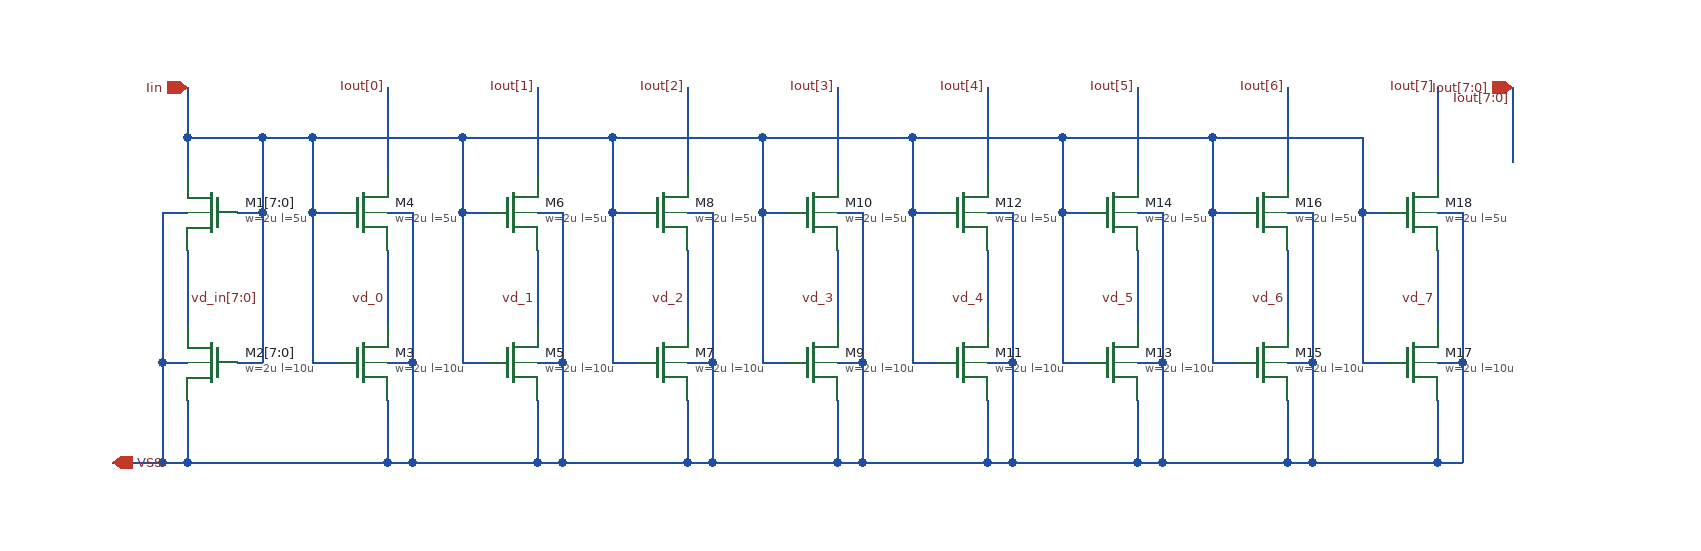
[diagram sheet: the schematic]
v {xschem version=3.4.7 file_version=1.2}
G {}
K {}
V {}
S {}
E {}
N 420 -320 440 -320 {lab=VSS}
N 420 -200 440 -200 {lab=VSS}
N 440 -320 440 -200 {lab=VSS}
N 420 -290 420 -230 {lab=vd_1}
N 300 -290 300 -230 {lab=vd_0}
N 140 -290 140 -230 {lab=vd_in[7:0]}
N 420 -170 420 -120 {lab=VSS}
N 140 -170 140 -120 {lab=VSS}
N 300 -170 300 -120 {lab=VSS}
N 300 -320 320 -320 {lab=VSS}
N 300 -200 320 -200 {lab=VSS}
N 320 -320 320 -200 {lab=VSS}
N 120 -320 140 -320 {lab=VSS}
N 120 -200 140 -200 {lab=VSS}
N 120 -320 120 -200 {lab=VSS}
N 140 -380 140 -350 {lab=Iin}
N 360 -320 360 -200 {lab=Iin}
N 360 -200 380 -200 {lab=Iin}
N 360 -320 380 -320 {lab=Iin}
N 360 -380 360 -320 {lab=Iin}
N 240 -320 240 -200 {lab=Iin}
N 240 -200 260 -200 {lab=Iin}
N 240 -320 260 -320 {lab=Iin}
N 240 -380 240 -320 {lab=Iin}
N 200 -320 200 -200 {lab=Iin}
N 180 -200 200 -200 {lab=Iin}
N 180 -320 200 -320 {lab=Iin}
N 200 -380 200 -320 {lab=Iin}
N 140 -380 200 -380 {lab=Iin}
N 120 -120 140 -120 {lab=VSS}
N 140 -420 140 -380 {lab=Iin}
N 300 -420 300 -350 {lab=Iout[0]}
N 420 -420 420 -350 {lab=Iout[1]}
N 120 -200 120 -120 {lab=VSS}
N 140 -120 300 -120 {lab=VSS}
N 200 -380 240 -380 {lab=Iin}
N 320 -120 420 -120 {lab=VSS}
N 240 -380 360 -380 {lab=Iin}
N 320 -200 320 -120 {lab=VSS}
N 300 -120 320 -120 {lab=VSS}
N 440 -200 440 -120 {lab=VSS}
N 660 -320 680 -320 {lab=VSS}
N 660 -200 680 -200 {lab=VSS}
N 680 -320 680 -200 {lab=VSS}
N 660 -290 660 -230 {lab=vd_3}
N 540 -290 540 -230 {lab=vd_2}
N 660 -170 660 -120 {lab=VSS}
N 540 -170 540 -120 {lab=VSS}
N 540 -320 560 -320 {lab=VSS}
N 540 -200 560 -200 {lab=VSS}
N 560 -320 560 -200 {lab=VSS}
N 600 -320 600 -200 {lab=Iin}
N 600 -200 620 -200 {lab=Iin}
N 600 -320 620 -320 {lab=Iin}
N 600 -380 600 -320 {lab=Iin}
N 480 -320 480 -200 {lab=Iin}
N 480 -200 500 -200 {lab=Iin}
N 480 -320 500 -320 {lab=Iin}
N 480 -380 480 -320 {lab=Iin}
N 600 -380 720 -380 {lab=Iin}
N 540 -420 540 -350 {lab=Iout[2]}
N 660 -420 660 -350 {lab=Iout[3]}
N 660 -120 680 -120 {lab=VSS}
N 560 -120 660 -120 {lab=VSS}
N 480 -380 600 -380 {lab=Iin}
N 560 -200 560 -120 {lab=VSS}
N 540 -120 560 -120 {lab=VSS}
N 680 -200 680 -120 {lab=VSS}
N 900 -320 920 -320 {lab=VSS}
N 900 -200 920 -200 {lab=VSS}
N 920 -320 920 -200 {lab=VSS}
N 900 -290 900 -230 {lab=vd_5}
N 780 -290 780 -230 {lab=vd_4}
N 900 -170 900 -120 {lab=VSS}
N 780 -170 780 -120 {lab=VSS}
N 780 -320 800 -320 {lab=VSS}
N 780 -200 800 -200 {lab=VSS}
N 800 -320 800 -200 {lab=VSS}
N 840 -320 840 -200 {lab=Iin}
N 840 -200 860 -200 {lab=Iin}
N 840 -320 860 -320 {lab=Iin}
N 840 -380 840 -320 {lab=Iin}
N 720 -320 720 -200 {lab=Iin}
N 720 -200 740 -200 {lab=Iin}
N 720 -320 740 -320 {lab=Iin}
N 720 -380 720 -320 {lab=Iin}
N 840 -380 960 -380 {lab=Iin}
N 780 -420 780 -350 {lab=Iout[4]}
N 900 -420 900 -350 {lab=Iout[5]}
N 900 -120 920 -120 {lab=VSS}
N 800 -120 900 -120 {lab=VSS}
N 720 -380 840 -380 {lab=Iin}
N 800 -200 800 -120 {lab=VSS}
N 780 -120 800 -120 {lab=VSS}
N 920 -200 920 -120 {lab=VSS}
N 1140 -320 1160 -320 {lab=VSS}
N 1140 -200 1160 -200 {lab=VSS}
N 1160 -320 1160 -200 {lab=VSS}
N 1140 -290 1140 -230 {lab=vd_7}
N 1020 -290 1020 -230 {lab=vd_6}
N 1140 -170 1140 -120 {lab=VSS}
N 1020 -170 1020 -120 {lab=VSS}
N 1020 -320 1040 -320 {lab=VSS}
N 1020 -200 1040 -200 {lab=VSS}
N 1040 -320 1040 -200 {lab=VSS}
N 1080 -320 1080 -200 {lab=Iin}
N 1080 -200 1100 -200 {lab=Iin}
N 1080 -320 1100 -320 {lab=Iin}
N 1080 -380 1080 -320 {lab=Iin}
N 960 -320 960 -200 {lab=Iin}
N 960 -200 980 -200 {lab=Iin}
N 960 -320 980 -320 {lab=Iin}
N 960 -380 960 -320 {lab=Iin}
N 1020 -420 1020 -350 {lab=Iout[6]}
N 1140 -420 1140 -350 {lab=Iout[0]}
N 1140 -120 1160 -120 {lab=VSS}
N 1040 -120 1140 -120 {lab=VSS}
N 960 -380 1080 -380 {lab=Iin}
N 1040 -200 1040 -120 {lab=VSS}
N 1020 -120 1040 -120 {lab=VSS}
N 1160 -200 1160 -120 {lab=VSS}
N 360 -380 480 -380 {lab=Iin}
N 440 -120 540 -120 {lab=VSS}
N 680 -120 780 -120 {lab=VSS}
N 920 -120 1020 -120 {lab=VSS}
N 420 -120 440 -120 {lab=VSS}
N 80 -120 120 -120 {lab=VSS}
N 1200 -420 1200 -360 {lab=Iout[7:0]}
C {title.sym} 160 0 0 0 {name=l1 author="Christoph Maier"}
C {sg13g2_pr/sg13_hv_nmos.sym} 160 -200 0 1 {name=M2[7:0]
l=10u
w=2u
ng=1
m=1
model=sg13_hv_nmos
spiceprefix=X
}
C {sg13g2_pr/sg13_hv_nmos.sym} 280 -200 0 0 {name=M3
l=10u
w=2u
ng=1
m=1
model=sg13_hv_nmos
spiceprefix=X
}
C {sg13g2_pr/sg13_hv_nmos.sym} 160 -320 0 1 {name=M1[7:0]
l=5u
w=2u
ng=1
m=1
model=sg13_hv_nmos
spiceprefix=X
}
C {sg13g2_pr/sg13_hv_nmos.sym} 280 -320 0 0 {name=M4
l=5u
w=2u
ng=1
m=1
model=sg13_hv_nmos
spiceprefix=X
}
C {sg13g2_pr/sg13_hv_nmos.sym} 400 -200 0 0 {name=M5
l=10u
w=2u
ng=1
m=1
model=sg13_hv_nmos
spiceprefix=X
}
C {sg13g2_pr/sg13_hv_nmos.sym} 400 -320 0 0 {name=M6
l=5u
w=2u
ng=1
m=1
model=sg13_hv_nmos
spiceprefix=X
}
C {iopin.sym} 80 -120 0 1 {name=p1 lab=VSS}
C {iopin.sym} 140 -420 3 0 {name=p3 lab=Iin}
C {iopin.sym} 1200 -420 3 0 {name=p4 lab=Iout[7:0]}
C {lab_wire.sym} 140 -250 0 1 {name=p6 lab=vd_in[7:0]}
C {lab_wire.sym} 300 -250 0 0 {name=p7 lab=vd_0}
C {lab_wire.sym} 420 -250 0 0 {name=p8 lab=vd_1}
C {sg13g2_pr/sg13_hv_nmos.sym} 520 -200 0 0 {name=M7
l=10u
w=2u
ng=1
m=1
model=sg13_hv_nmos
spiceprefix=X
}
C {sg13g2_pr/sg13_hv_nmos.sym} 520 -320 0 0 {name=M8
l=5u
w=2u
ng=1
m=1
model=sg13_hv_nmos
spiceprefix=X
}
C {sg13g2_pr/sg13_hv_nmos.sym} 640 -200 0 0 {name=M9
l=10u
w=2u
ng=1
m=1
model=sg13_hv_nmos
spiceprefix=X
}
C {sg13g2_pr/sg13_hv_nmos.sym} 640 -320 0 0 {name=M10
l=5u
w=2u
ng=1
m=1
model=sg13_hv_nmos
spiceprefix=X
}
C {lab_wire.sym} 540 -250 0 0 {name=p10 lab=vd_2}
C {lab_wire.sym} 660 -250 0 0 {name=p11 lab=vd_3}
C {sg13g2_pr/sg13_hv_nmos.sym} 760 -200 0 0 {name=M11
l=10u
w=2u
ng=1
m=1
model=sg13_hv_nmos
spiceprefix=X
}
C {sg13g2_pr/sg13_hv_nmos.sym} 760 -320 0 0 {name=M12
l=5u
w=2u
ng=1
m=1
model=sg13_hv_nmos
spiceprefix=X
}
C {sg13g2_pr/sg13_hv_nmos.sym} 880 -200 0 0 {name=M13
l=10u
w=2u
ng=1
m=1
model=sg13_hv_nmos
spiceprefix=X
}
C {sg13g2_pr/sg13_hv_nmos.sym} 880 -320 0 0 {name=M14
l=5u
w=2u
ng=1
m=1
model=sg13_hv_nmos
spiceprefix=X
}
C {lab_wire.sym} 780 -250 0 0 {name=p14 lab=vd_4}
C {lab_wire.sym} 900 -250 0 0 {name=p15 lab=vd_5}
C {sg13g2_pr/sg13_hv_nmos.sym} 1000 -200 0 0 {name=M15
l=10u
w=2u
ng=1
m=1
model=sg13_hv_nmos
spiceprefix=X
}
C {sg13g2_pr/sg13_hv_nmos.sym} 1000 -320 0 0 {name=M16
l=5u
w=2u
ng=1
m=1
model=sg13_hv_nmos
spiceprefix=X
}
C {sg13g2_pr/sg13_hv_nmos.sym} 1120 -200 0 0 {name=M17
l=10u
w=2u
ng=1
m=1
model=sg13_hv_nmos
spiceprefix=X
}
C {sg13g2_pr/sg13_hv_nmos.sym} 1120 -320 0 0 {name=M18
l=5u
w=2u
ng=1
m=1
model=sg13_hv_nmos
spiceprefix=X
}
C {lab_wire.sym} 1020 -250 0 0 {name=p18 lab=vd_6}
C {lab_wire.sym} 1140 -250 0 0 {name=p19 lab=vd_7}
C {lab_pin.sym} 300 -420 0 0 {name=p2 lab=Iout[0]}
C {lab_pin.sym} 420 -420 0 0 {name=p5 lab=Iout[1]}
C {lab_pin.sym} 540 -420 0 0 {name=p9 lab=Iout[2]}
C {lab_pin.sym} 660 -420 0 0 {name=p13 lab=Iout[3]}
C {lab_pin.sym} 780 -420 0 0 {name=p16 lab=Iout[4]}
C {lab_pin.sym} 900 -420 0 0 {name=p17 lab=Iout[5]}
C {lab_pin.sym} 1020 -420 0 0 {name=p20 lab=Iout[6]}
C {lab_pin.sym} 1140 -420 0 0 {name=p21 lab=Iout[7]}
C {lab_wire.sym} 1200 -410 3 0 {name=p22 lab=Iout[7:0]}
